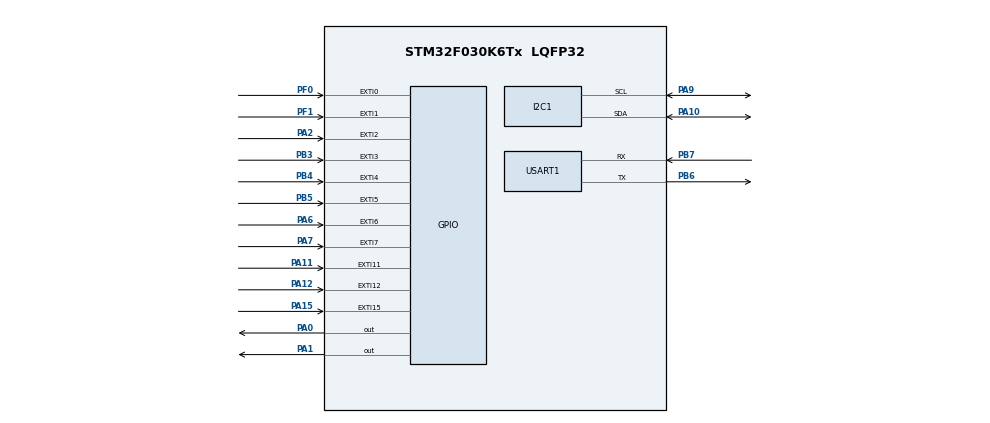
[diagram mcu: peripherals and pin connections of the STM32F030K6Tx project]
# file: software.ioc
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Mcu.Family=STM32F0
Mcu.Name=STM32F030K6Tx
Mcu.Package=LQFP32
PA0.Signal=GPIO_Output
PA1.Signal=GPIO_Output
PA10.Mode=I2C
PA10.Signal=I2C1_SDA
PA11.Signal=GPXTI11
PA12.Signal=GPXTI12
PA13.Mode=Serial_Wire
PA13.Signal=SYS_SWDIO
PA14.Mode=Serial_Wire
PA14.Signal=SYS_SWCLK
PA15.Signal=GPXTI15
PA2.Signal=GPXTI2
PA6.Signal=GPXTI6
PA7.Signal=GPXTI7
PA9.Mode=I2C
PA9.Signal=I2C1_SCL
PB3.Signal=GPXTI3
PB4.Signal=GPXTI4
PB5.Signal=GPXTI5
PB6.Mode=Asynchronous
PB6.Signal=USART1_TX
PB7.Mode=Asynchronous
PB7.Signal=USART1_RX
PF0-OSC_IN.Signal=GPXTI0
PF1-OSC_OUT.Signal=GPXTI1
ProjectManager.HeapSize=0x200
ProjectManager.StackSize=0x400
ProjectManager.TargetToolchain=EWARM V8
USART1.VirtualMode-Asynchronous=VM_ASYNC
board=custom

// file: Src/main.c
/* USER CODE BEGIN Header */
/**
  ******************************************************************************
  * @file           : main.c
  * @brief          : Main program body
  ******************************************************************************
  ** This notice applies to any and all portions of this file
  * that are not between comment pairs USER CODE BEGIN and
  * USER CODE END. Other portions of this file, whether
  * inserted by the user or by software development tools
  * are owned by their respective copyright owners.
  *
  * COPYRIGHT(c) 2019 STMicroelectronics
  *
  * Redistribution and use in source and binary forms, with or without modification,
  * are permitted provided that the following conditions are met:
  *   1. Redistributions of source code must retain the above copyright notice,
  *      this list of conditions and the following disclaimer.
  *   2. Redistributions in binary form must reproduce the above copyright notice,
  *      this list of conditions and the following disclaimer in the documentation
  *      and/or other materials provided with the distribution.
  *   3. Neither the name of STMicroelectronics nor the names of its contributors
  *      may be used to endorse or promote products derived from this software
  *      without specific prior written permission.
  *
  * THIS SOFTWARE IS PROVIDED BY THE COPYRIGHT HOLDERS AND CONTRIBUTORS "AS IS"
  * AND ANY EXPRESS OR IMPLIED WARRANTIES, INCLUDING, BUT NOT LIMITED TO, THE
  * IMPLIED WARRANTIES OF MERCHANTABILITY AND FITNESS FOR A PARTICULAR PURPOSE ARE
  * DISCLAIMED. IN NO EVENT SHALL THE COPYRIGHT HOLDER OR CONTRIBUTORS BE LIABLE
  * FOR ANY DIRECT, INDIRECT, INCIDENTAL, SPECIAL, EXEMPLARY, OR CONSEQUENTIAL
  * DAMAGES (INCLUDING, BUT NOT LIMITED TO, PROCUREMENT OF SUBSTITUTE GOODS OR
  * SERVICES; LOSS OF USE, DATA, OR PROFITS; OR BUSINESS INTERRUPTION) HOWEVER
  * CAUSED AND ON ANY THEORY OF LIABILITY, WHETHER IN CONTRACT, STRICT LIABILITY,
  * OR TORT (INCLUDING NEGLIGENCE OR OTHERWISE) ARISING IN ANY WAY OUT OF THE USE
  * OF THIS SOFTWARE, EVEN IF ADVISED OF THE POSSIBILITY OF SUCH DAMAGE.
  *
  ******************************************************************************
  */
/* USER CODE END Header */

#include "main.h"

I2C_HandleTypeDef hi2c1;

UART_HandleTypeDef huart1;

void SystemClock_Config(void);
static void MX_GPIO_Init(void);
static void MX_I2C1_Init(void);
static void MX_USART1_UART_Init(void);

int main(void)
{

  /* MCU Configuration--------------------------------------------------------*/

  /* Reset of all peripherals, Initializes the Flash interface and the Systick. */
  HAL_Init();

  /* Configure the system clock */
  SystemClock_Config();

  /* Initialize all configured peripherals */
  MX_GPIO_Init();
  MX_I2C1_Init();
  MX_USART1_UART_Init();

  /* Infinite loop */
  while (1)
  {

  }
}

void SystemClock_Config(void)
{
  RCC_OscInitTypeDef RCC_OscInitStruct = {0};
  RCC_ClkInitTypeDef RCC_ClkInitStruct = {0};
  RCC_PeriphCLKInitTypeDef PeriphClkInit = {0};

  /**Initializes the CPU, AHB and APB busses clocks
  */
  RCC_OscInitStruct.OscillatorType = RCC_OSCILLATORTYPE_HSI;
  RCC_OscInitStruct.HSIState = RCC_HSI_ON;
  RCC_OscInitStruct.HSICalibrationValue = RCC_HSICALIBRATION_DEFAULT;
  RCC_OscInitStruct.PLL.PLLState = RCC_PLL_NONE;
  if (HAL_RCC_OscConfig(&RCC_OscInitStruct) != HAL_OK)
  {
    Error_Handler();
  }
  /**Initializes the CPU, AHB and APB busses clocks
  */
  RCC_ClkInitStruct.ClockType = RCC_CLOCKTYPE_HCLK|RCC_CLOCKTYPE_SYSCLK
                              |RCC_CLOCKTYPE_PCLK1;
  RCC_ClkInitStruct.SYSCLKSource = RCC_SYSCLKSOURCE_HSI;
  RCC_ClkInitStruct.AHBCLKDivider = RCC_SYSCLK_DIV1;
  RCC_ClkInitStruct.APB1CLKDivider = RCC_HCLK_DIV1;

  if (HAL_RCC_ClockConfig(&RCC_ClkInitStruct, FLASH_LATENCY_0) != HAL_OK)
  {
    Error_Handler();
  }
  PeriphClkInit.PeriphClockSelection = RCC_PERIPHCLK_USART1|RCC_PERIPHCLK_I2C1;
  PeriphClkInit.Usart1ClockSelection = RCC_USART1CLKSOURCE_PCLK1;
  PeriphClkInit.I2c1ClockSelection = RCC_I2C1CLKSOURCE_HSI;
  if (HAL_RCCEx_PeriphCLKConfig(&PeriphClkInit) != HAL_OK)
  {
    Error_Handler();
  }
}

static void MX_I2C1_Init(void)
{

  hi2c1.Instance = I2C1;
  hi2c1.Init.Timing = 0x2000090E;
  hi2c1.Init.OwnAddress1 = 0;
  hi2c1.Init.AddressingMode = I2C_ADDRESSINGMODE_7BIT;
  hi2c1.Init.DualAddressMode = I2C_DUALADDRESS_DISABLE;
  hi2c1.Init.OwnAddress2 = 0;
  hi2c1.Init.OwnAddress2Masks = I2C_OA2_NOMASK;
  hi2c1.Init.GeneralCallMode = I2C_GENERALCALL_DISABLE;
  hi2c1.Init.NoStretchMode = I2C_NOSTRETCH_DISABLE;
  if (HAL_I2C_Init(&hi2c1) != HAL_OK)
  {
    Error_Handler();
  }
  /**Configure Analogue filter
  */
  if (HAL_I2CEx_ConfigAnalogFilter(&hi2c1, I2C_ANALOGFILTER_ENABLE) != HAL_OK)
  {
    Error_Handler();
  }
  /**Configure Digital filter
  */
  if (HAL_I2CEx_ConfigDigitalFilter(&hi2c1, 0) != HAL_OK)
  {
    Error_Handler();
  }

}

static void MX_USART1_UART_Init(void)
{

  huart1.Instance = USART1;
  huart1.Init.BaudRate = 38400;
  huart1.Init.WordLength = UART_WORDLENGTH_8B;
  huart1.Init.StopBits = UART_STOPBITS_1;
  huart1.Init.Parity = UART_PARITY_NONE;
  huart1.Init.Mode = UART_MODE_TX_RX;
  huart1.Init.HwFlowCtl = UART_HWCONTROL_NONE;
  huart1.Init.OverSampling = UART_OVERSAMPLING_16;
  huart1.Init.OneBitSampling = UART_ONE_BIT_SAMPLE_DISABLE;
  huart1.AdvancedInit.AdvFeatureInit = UART_ADVFEATURE_NO_INIT;
  if (HAL_UART_Init(&huart1) != HAL_OK)
  {
    Error_Handler();
  }

}

static void MX_GPIO_Init(void)
{
  GPIO_InitTypeDef GPIO_InitStruct = {0};

  /* GPIO Ports Clock Enable */
  __HAL_RCC_GPIOA_CLK_ENABLE();
  __HAL_RCC_GPIOB_CLK_ENABLE();

  /*Configure GPIO pins : PA2 PA3 PA4 PA5
                           PA6 PA7 PA8 PA11
                           PA12 PA13 PA14 PA15 */
  GPIO_InitStruct.Pin = GPIO_PIN_2|GPIO_PIN_3|GPIO_PIN_4|GPIO_PIN_5
                          |GPIO_PIN_6|GPIO_PIN_7|GPIO_PIN_8|GPIO_PIN_11
                          |GPIO_PIN_12|GPIO_PIN_13|GPIO_PIN_14|GPIO_PIN_15;
  GPIO_InitStruct.Mode = GPIO_MODE_IT_RISING;
  GPIO_InitStruct.Pull = GPIO_NOPULL;
  HAL_GPIO_Init(GPIOA, &GPIO_InitStruct);

  /*Configure GPIO pins : PB0 PB1 */
  GPIO_InitStruct.Pin = GPIO_PIN_0|GPIO_PIN_1;
  GPIO_InitStruct.Mode = GPIO_MODE_IT_RISING;
  GPIO_InitStruct.Pull = GPIO_NOPULL;
  HAL_GPIO_Init(GPIOB, &GPIO_InitStruct);

}

void Error_Handler(void)
{
}

/************************ (C) COPYRIGHT STMicroelectronics *****END OF FILE****/
